VERSION 5.8 ;
BUSBITCHARS "[]" ;

# An L-shaped hard macro.  LEF has no polygonal MACRO SIZE, so SIZE is the
# bounding box and the real outline is carried by the OVERLAP-layer
# obstruction, which LEF/DEF defines as the occupied area of a
# non-rectangular macro.  The notch (x >= 28.5, y >= 21) is not part of the
# macro: nothing is drawn there and no supply pin reaches into it.
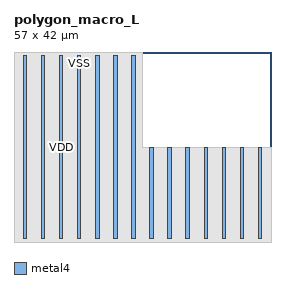
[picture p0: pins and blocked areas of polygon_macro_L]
MACRO polygon_macro_L
  CLASS BLOCK ;
  FOREIGN polygon_macro_L 0 0 ;
  ORIGIN 0 0 ;
  SYMMETRY X Y R90 ;
  SIZE 57.000 BY 42.000 ;
  PIN VDD
    DIRECTION INOUT ;
    USE POWER ;
    PORT
      LAYER metal4 ;
      RECT 2.000 0.700 2.800 41.300 ;
      RECT 10.000 0.700 10.800 41.300 ;
      RECT 18.000 0.700 18.800 41.300 ;
      RECT 26.000 0.700 26.800 41.300 ;
      RECT 34.000 0.700 34.800 21.000 ;
      RECT 42.000 0.700 42.800 21.000 ;
      RECT 50.000 0.700 50.800 21.000 ;
    END
  END VDD
  PIN VSS
    DIRECTION INOUT ;
    USE GROUND ;
    PORT
      LAYER metal4 ;
      RECT 6.000 0.700 6.800 41.300 ;
      RECT 14.000 0.700 14.800 41.300 ;
      RECT 22.000 0.700 22.800 41.300 ;
      RECT 30.000 0.700 30.800 21.000 ;
      RECT 38.000 0.700 38.800 21.000 ;
      RECT 46.000 0.700 46.800 21.000 ;
      RECT 54.000 0.700 54.800 21.000 ;
    END
  END VSS
  OBS
    LAYER metal1 ;
      POLYGON 0.000 0.000 57.000 0.000 57.000 21.000 28.500 21.000 28.500 42.000 0.000 42.000 ;
    LAYER metal2 ;
      POLYGON 0.000 0.000 57.000 0.000 57.000 21.000 28.500 21.000 28.500 42.000 0.000 42.000 ;
    LAYER metal3 ;
      POLYGON 0.000 0.000 57.000 0.000 57.000 21.000 28.500 21.000 28.500 42.000 0.000 42.000 ;
    LAYER OVERLAP ;
      POLYGON 0.000 0.000 57.000 0.000 57.000 21.000 28.500 21.000 28.500 42.000 0.000 42.000 ;
  END
END polygon_macro_L

END LIBRARY
